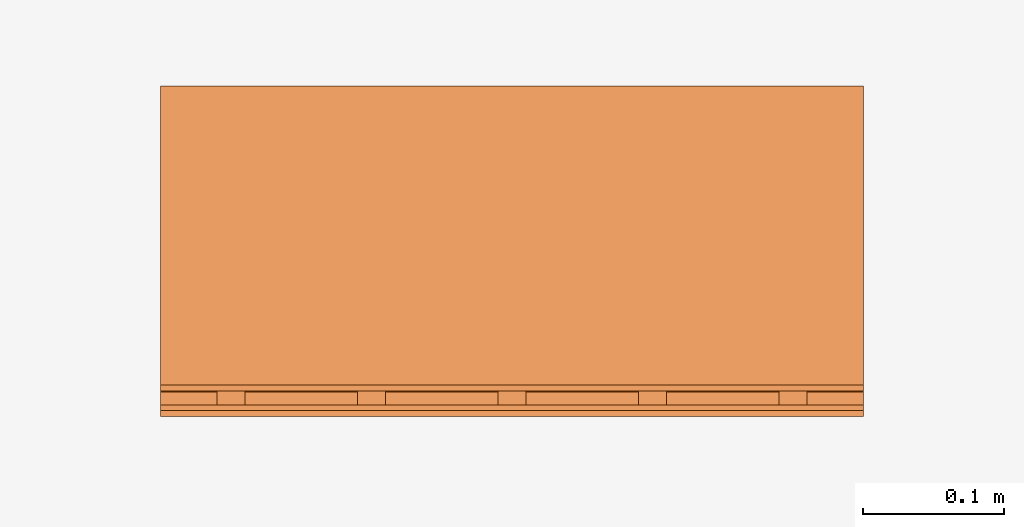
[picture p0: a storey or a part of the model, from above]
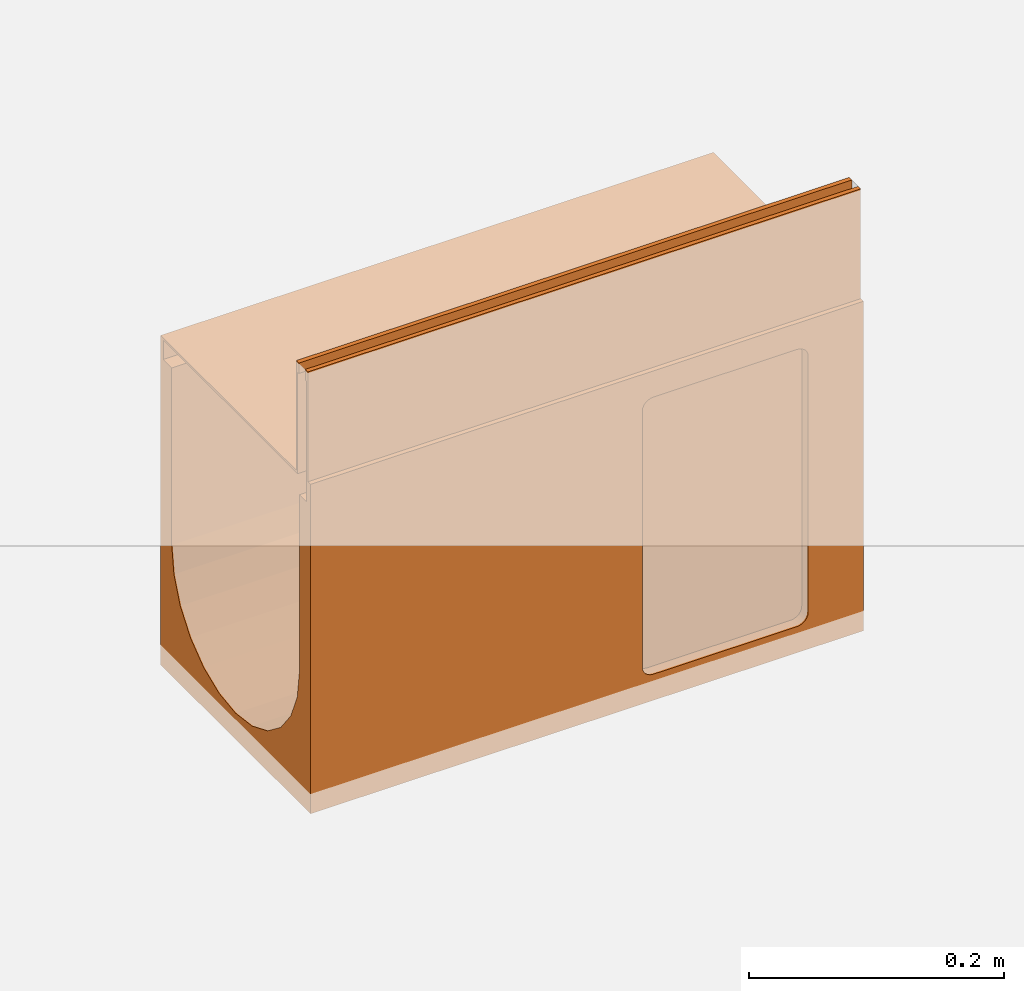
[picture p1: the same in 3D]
Properties of the parts of a building model (IFC2X3)

# File
Description: ViewDefinition [CoordinationView]
File name: 24214 - No 10.1J Constant Depth Channel - 500mm LG - Invert Depth 290mm.ifc
Time: 2013-10-30T14:06:25
Written by: Autodesk Revit 2013
Made in: 20120221_2030(x64)

# IfcProject, Project Number
LongName: Project Name; Phase: Project Status

# IfcSite, Default
RefLatitude: 42, 21, 30, 344238; RefLongitude: -71, -3, -35, -194702; RefElevation: 0 mm

# IfcBuilding
Pset_BuildingCommon - NumberOfStoreys: 1
Other - Project Name: Project Name; Client Name: Owner; Project Status: Project Status; Project Number: Project Number; Project Address: ## Street City, State Zip; Project Issue Date: Issue Date

# IfcBuildingStorey, Level 1
LongName: Level 1; Elevation: 0 mm
Constraints - Elevation Base: 0; Elevation: 0 mm
Graphics - Color: 0; Line Weight: 1; Symbol: M_Level Head - Circle: M_Level Head - Circle; Line Pattern: Center; Symbol at End 2 Default: yes; Symbol at End 1 Default: no
Dimensions - Computation Height: 0 mm
Identity Data - Name: Level 1; Building Story: yes; Structural: no

# IfcBuildingElementProxy: 24214 - No 10.1J Constant Depth Channel - 500mm LG - Invert Depth 290mm, Civil-Drainage-Channel-ACO-MultiDrain-M200DS-Brickslot-Channel-System:24214 - No 10.1J Constant Depth Channel - 500mm LG - Invert Depth 290mm:24214 - No 10.1J Constant Depth Channel - 500mm LG - Invert Depth 290mm:196059
In: Level 1
Material: Stainless Steel (F), Vienite® Synthetic Resin Concrete
Dimensions - Length: 1000 mm; FloorCut_Length: -500 mm; Brickslot Void Length: -500 mm; Brickslot Grating Void Depth: 0 mm; Brickslot Access Unit Void Bottom Depth: 6105 mm; Volume: 9508837 mm3; Custom_Void_Length: 0 mm; Brickslot Access Unit Void Depth: 6000 mm; EndCap Position: 500 mm; Depth: 315 mm; Length Drain: -500 mm; FloorCut_Depth: 315 mm; InvDepth: 190 mm; FloorCut_Width: 235 mm; EndCap_Height: 315 mm; FloorCut_HorPosition: 117.5 mm
Construction - 409000_Load Class C250 & D400_Brickslot_Access Unit_Stainless Steel_500mm Long: no; 408999_Load Class C250 & D400_Brickslot Grating_Stainless Steel_500mm Long: yes; 23219 - Universal Endcap (Female End): no; 408998_Load Class C250 & D400_Brickslot Grating_Stainless Steel_1000mm Long: no; 23219 - Universal Endcap (Male End): no; Shallow Depth Channel: no; 23410_Sump Unit: no; Shallow Depth Channel with seal: no; Constant Depth Channel_500: yes; Constant Depth Channel_1000: no
Constraints - Level: Level: Level 1; Moves With Nearby Elements: no
Phasing - Phase Created: New Construction
Pset_BuildingElementProxyCommon - Reference: 24214 - No 10.1J Constant Depth Channel - 500mm LG - Invert Depth 290mm
General - SerialNumber: 0; TagNumber: 0
Data - Channel C.S.A: 0.043m²; Concrete Surround Volume - Load Class B 125 - C 250 - Concrete Pavement: 0.19m³/m; Hydraulic Performance: http://www.aco.co.uk/download.php?id=173; Installation - Concrete Grade: Refer to brochure; Concrete Surround Volume - Load Class D 400 - Concrete Pavement: 0.26m³/m; Invert Depth: 290mm; ACO Hydraulic Design Software: http://www.acodesign.co.uk; Product Dimensions: 500mm x 235mm x 315mm (LxWxH); Load Class: A 15 - D 400; Product Weight: 20.9 Kg; Concrete Surround Volume - Load Class A 15 - Concrete Pavement: 0.12m³/m; Product Standard: BS EN 1433:2002, CE marked
Identity Data - Installation guidelines: http://www.aco.co.uk/download.php?id=173; Product brochure: http://www.aco.co.uk/download.php?id=173; Fax: +44 (0)1462 815895; e-mail Technical: technical@aco.co.uk; Telephone: +44 (0)1462 816666; e-mail Sales: customersupport@aco.co.uk; Product Code: 24214; Price: POA - contact ACO; Model: ACO MultiDrain MDS Brickslot - M200DS; Product Page URL: http://www.aco.co.uk/product_detail.php?id=58; Type Comments: ACO MultiDrain M200DS 10.1J Constant Depth Channel 500mm Long; OmniClass Number: 23.70.50.24; Manufacturer: ACO Technologies plc - ACO Water Management Division; Assembly Code: D2040; Cost: 0; Address: ACO Business Park, Hitchin Road, Shefford, Bedfordshire, United Kingdom SG17 5TE; Maintenance guidelines: http://www.aco.co.uk/download.php?id=173; Model Description: Channel drainage system; Watermarked By: www.aco.co.uk; OmniClass Title: Rainwater Removal; Watermark 1: This file is the property of ACO Technologies PLC; Watermarked With: BIM Manager Premium Suite; Watermark 2: This file is water marked and users are prohibited to reproduce, adapt, distribute this information; URL: www.aco.co.uk; Assembly Description: Rain Water Drainage
Model Properties - Brickslot Grating Product code 408998: N/A; Brickslot Access Unit Product code 409000: Load Class C250/D400 - Brickslot Access Unit Stainless Steel - 500mm long x 105mm high - 10mm Slot - Intake area 10000mm²/m - 8.5 Kg; Brickslot Grating Product code 408999: Load Class C250/D400 - Brickslot Stainless Steel - 500mm long x 105mm high - 10mm Slot - Intake area 10000mm²/m - 4.8kg; End Cap Product code 23219: No 306 Universal End Cap - 235mm wide x 365mm long - Spigot Ø160mm x 75mm long - Silver - Polypropylene - 0.4kg
Green Building Properties - Edge Rail Recycled Material Content: Between 40% - 90%; Edge Rail Recyclable: Fully recyclable; Channel Recyclable: Fully recyclable; Channel Recycled Material Content: 20% minimum
Other - Revision: 1; CreatedBy: www.aco.co.uk
Materials and Finishes - Edge Rail Material: Stainless Steel Grade 304; Channel Material: Vienite® Synthetic Resin Concrete; Edge Rail Colour: Self; Channel Colour: Brown

# IfcOpeningElement: Opening (2)
In: Level 1
Dimensions - Thickness: 400 mm; Volume: 9964392500 mm3; Perimeter: 20000 mm; Area: 24991000 mm2
Constraints - Level: Level: Level 1; Room Bounding: yes; Height Offset From Level: 0 mm; Related to Mass: no
Phasing - Phase Created: New Construction
Structural - Enable Analytical Model: no; Structural: no
Analytical Properties - Thermal Resistance (R): 0.477897; Thermal mass: 543920; Absorptance: 0.1; Heat Transfer Coefficient (U): 2.0925; Roughness: 1
Construction - Default Thickness: 400 mm; Function: 0
Materials and Finishes - Structural Material: Earth
Graphics - Coarse Scale Fill Color: 0

# IfcSlab: Floor:Generic Floor - 400mm, Floor:Generic Floor - 400mm:193825
In: Level 1
PredefinedType: FLOOR; Material: Earth 400 mm
Dimensions - Thickness: 400 mm; Volume: 9964392500 mm3; Perimeter: 20000 mm; Area: 24991000 mm2
Constraints - Level: Level: Level 1; Room Bounding: yes; Height Offset From Level: 0 mm; Related to Mass: no
Phasing - Phase Created: New Construction
Structural - Enable Analytical Model: no; Structural: no
Pset_SlabCommon - Reference: Generic Floor - 400mm; IsExternal: no; LoadBearing: yes
Analytical Properties - Thermal Resistance (R): 0.477897; Thermal mass: 543920; Absorptance: 0.1; Heat Transfer Coefficient (U): 2.0925; Roughness: 1
Construction - Default Thickness: 400 mm; Function: 0
Materials and Finishes - Structural Material: Earth
Graphics - Coarse Scale Fill Color: 0
